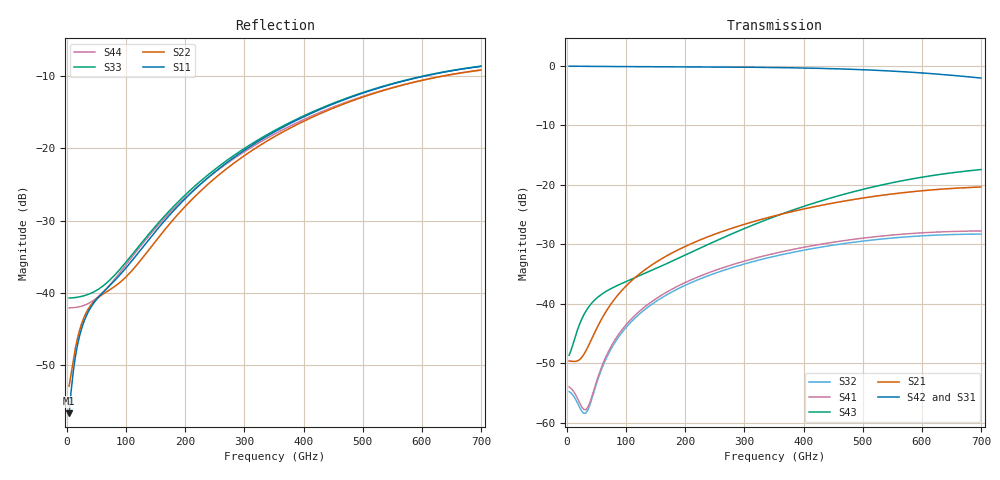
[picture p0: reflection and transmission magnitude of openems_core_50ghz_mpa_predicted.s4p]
#  Hz  S  RI  R  50
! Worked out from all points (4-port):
!   200 points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, 3.5 GHz to 700 GHz, reference 50 ohm
!   strongest paths, dB at 3.5 GHz, 178.5 GHz, 353.5 GHz, 528.5 GHz, 700 GHz:
!     S42: -0.1, -0.2, -0.3, -0.8, -2.1
!     S31: -0.1, -0.2, -0.3, -0.9, -2.2
!     S21: -49.6, -31.4, -25.2, -21.8, -20.4
!     S43: -48.6, -32.8, -25.3, -20.1, -17.4
!     S41: -54.0, -37.5, -31.5, -28.7, -27.8
!     S32: -54.8, -38.0, -32.0, -29.2, -28.3
!   lowest |S11| = -56.7 dB at 3.5 GHz (marker M1), VSWR 1.00, Z = 50.1 + j0.0728 ohm
!   |S11| at or under -10 dB: start of sweep to 603.3 GHz
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3.5e9  0.00127 0.000727  0.00346 0.000217  0.9915 -0.00845  0.00201 1.33e-05
       0.0033 0.00024  0.00215 0.000688  0.0019 3.11e-05  0.9924 -0.0085
       0.9916 -0.0085  0.00183 7.67e-07  0.00917 -0.000907  -0.00332 0.00121
       0.002 -4.88e-06  0.9923 -0.00854  -0.00349 0.00123  0.00785 -0.000613
1.75e10  0.00339 0.00267  0.00314 0.00127  0.9896 -0.0418  0.00163 0.000237
         0.00301 0.00137  0.00408 0.00257  0.00154 0.000317  0.9905 -0.0421
         0.9898 -0.0421  0.00146 0.000166  0.00836 -0.00415  -0.00194 0.00554
         0.0016 0.00015  0.9904 -0.0423  -0.00207 0.00564  0.00745 -0.00283
3.85e10  0.00769 0.00083  0.00263 0.00377  0.9838 -0.0897  0.000838 0.00143
         0.00262 0.00389  0.00797 0.00105  0.00081 0.00155  0.9846 -0.0903
         0.9842 -0.0906  0.000704 0.00122  0.00683 -0.00711  0.00135 0.00945
         0.000782 0.00125  0.9846 -0.0908  0.00132 0.00959  0.00691 -0.00505
1.05e11  0.000715 -0.0158  0.00671 0.0134  0.9548 -0.2335  0.00185 0.00732
         0.00683 0.0133  0.00145 -0.0135  0.0019 0.00746  0.9554 -0.2349
         0.9547 -0.2366  0.00158 0.00658  0.0113 -0.0132  0.0059 0.0146
         0.00169 0.00692  0.9552 -0.2367  0.00594 0.0146  0.0126 -0.011
2.415e11  -0.064 -0.00638  0.0315 0.0199  0.831 -0.5117  0.0135 0.0138
          0.0315 0.0196  -0.058 -0.00293  0.0135 0.0141  0.8305 -0.5147
          0.8269 -0.518  0.0122 0.0124  0.0398 -0.0541  0.00675 0.0312
          0.0129 0.0131  0.8287 -0.5186  0.00646 0.0314  0.0402 -0.0499
4.9e11  -0.1083 0.2073  0.0681 -0.0345  0.3583 -0.8553  0.0362 -0.00477
        0.0676 -0.0348  -0.0951 0.1977  0.0365 -0.00403  0.3541 -0.8592
        0.3449 -0.8576  0.0328 -0.00484  -0.0033 -0.2361  0.0406 0.0777
        0.0347 -0.0055  0.3469 -0.8637  0.0402 0.0792  0.000609 -0.2221
7e11  0.1111 0.3531  0.0246 -0.0929  -0.1343 -0.7721  0.0259 -0.0334
      0.0239 -0.0928  0.1128 0.3309  0.0269 -0.0326  -0.1412 -0.7735
      -0.1475 -0.7646  0.0229 -0.0309  -0.2249 -0.2955  0.1097 0.0733
      0.0239 -0.0332  -0.1515 -0.7737  0.1109 0.0757  -0.2078 -0.2794
